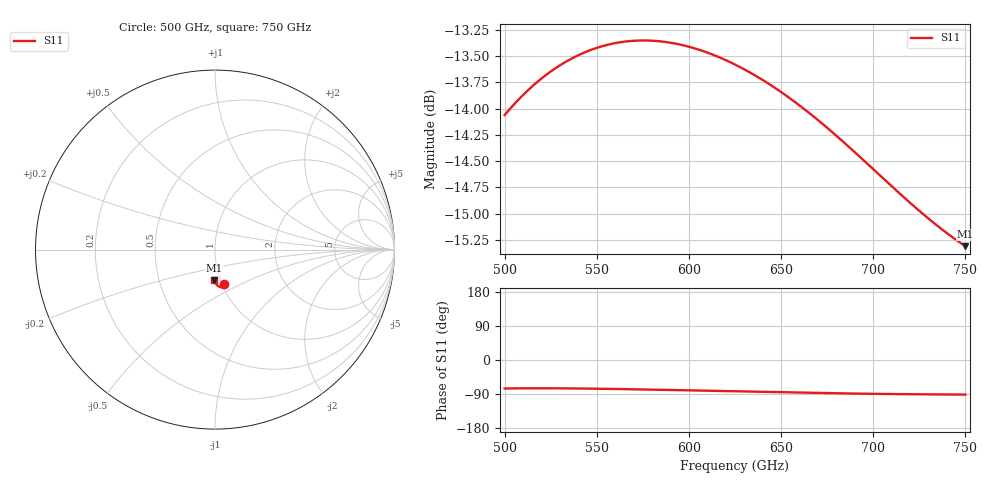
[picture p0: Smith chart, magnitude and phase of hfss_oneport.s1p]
! Touchstone file from project reactangularAPerture
! Exported from HFSS 11.1
!Data is not renormalized
# GHZ S MA
! Modal data exported
! Port[1] = WavePort1:1
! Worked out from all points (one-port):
!   401 points, 500 GHz to 750 GHz, reference per port
!   lowest |S11| = -15.3 dB at 750 GHz (marker M1), VSWR 1.41
!   |S11| at or under -10 dB: start of sweep to end of sweep
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500  0.1981 -75.1
! Gamma 0.000000000000000E+00 6.467109117238500E+03
! Port Impedance 3.763664694078020E+02 0.000000000000000E+00
501.25  0.1987 -75.0
508.75  0.202 -74.7
516.25  0.2049 -74.6
523.75  0.2074 -74.6
531.25  0.2095 -74.8
538.75  0.2113 -75.1
546.875  0.2128 -75.5
554.375  0.2138 -76.0
562.5  0.2145 -76.7
570  0.2149 -77.3
578.125  0.2149 -78.0
585.625  0.2147 -78.7
593.75  0.2141 -79.5
601.25  0.2133 -80.2
609.375  0.2122 -81.1
616.875  0.211 -81.8
625  0.2094 -82.7
632.5  0.2077 -83.4
640.625  0.2057 -84.3
656.25  0.2013 -85.8
671.25  0.1966 -87.1
687.5  0.1911 -88.5
703.125  0.1856 -89.5
718.75  0.1804 -90.3
736.25  0.1751 -90.9
745  0.1728 -91.2
750  0.1716 -91.3
